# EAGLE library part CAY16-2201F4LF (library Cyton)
Bourns CAY16 Series 2.2k +/-1% Isolated SMT Resistor Array, 4 Resistors, 0.25W total 1206 Package Convex Source: Datasheet

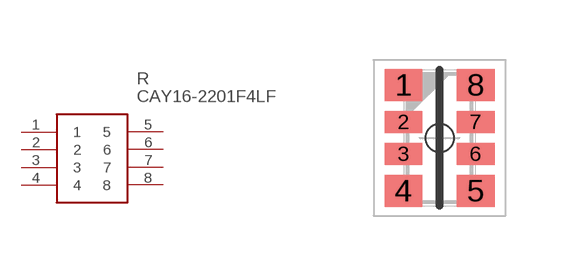
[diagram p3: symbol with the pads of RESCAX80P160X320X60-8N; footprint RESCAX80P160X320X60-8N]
Designator prefix R

## CAY16-2201F4LF (DESCRIPTION: Bourns CAY16 Series 2.2k +/-1% Isolated SMT Resistor Array, 4 Resistors, 0.25W total 1206 Package Convex; HEIGHT: 0.6mm; MANUFACTURER_NAME: Bourns; MANUFACTURER_PART_NUMBER: CAY16-2201F4LF; RS_PART_NUMBER: 7408773P; RS_PRICE-STOCK: http://uk.rs-online.com/web/p/products/7408773P)  [RESCAX80P160X320X60-8N]
1  1
2  2
3  3
4  4
5  5
6  6
7  7
8  8

## Footprint RESCAX80P160X320X60-8N (pad centres in mm)
CAY16-4701F4LF
smd 0.95 x 0.8: 1 -0.9,1.325; 4 -0.9,-1.325; 5 0.9,-1.325; 8 0.9,1.325
smd 0.95 x 0.55: 2 -0.9,0.4; 3 -0.9,-0.4; 6 0.9,-0.4; 7 0.9,0.4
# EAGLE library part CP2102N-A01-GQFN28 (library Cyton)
Ic Bridge Usb To Uart 28qfn

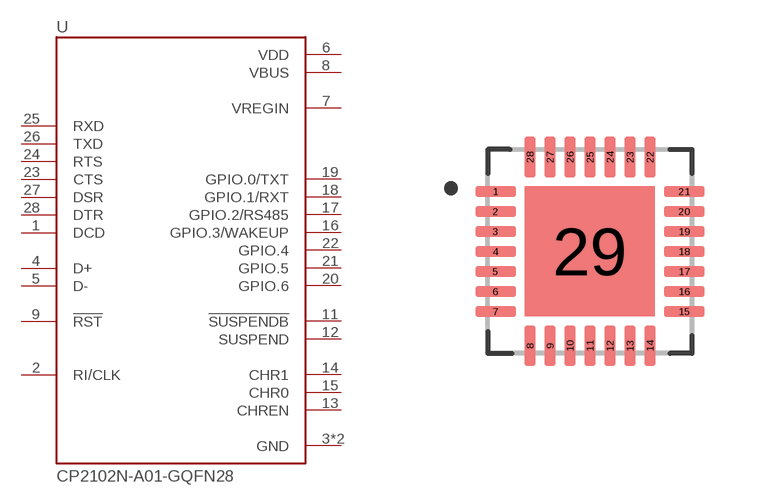
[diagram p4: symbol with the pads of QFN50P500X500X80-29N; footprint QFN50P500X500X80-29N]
Designator prefix U

## CP2102N-A01-GQFN28 (AVAILABILITY: Unavailable; DESCRIPTION: Usb-Uart Interface Bridge, Qfn-28; MF: Silicon Labs; MP: CP2102N-A01-GQFN28; PACKAGE: QFN-28 Silicon Labs; PRICE: None)  [QFN50P500X500X80-29N]
1  DCD  in
2  RI/CLK
3  GND  pwr
4  D+
5  D-
6  VDD  pwr
7  VREGIN  pwr
8  VBUS  pwr
9  !RST  in
11  !SUSPENDB  out
12  SUSPEND  out
13  CHREN  out
14  CHR1  out
15  CHR0  out
16  GPIO.3/WAKEUP
17  GPIO.2/RS485
18  GPIO.1/RXT
19  GPIO.0/TXT
20  GPIO.6
21  GPIO.5
22  GPIO.4
23  CTS  in
24  RTS  out
25  RXD  in
26  TXD  out
27  DSR  in
28  DTR  out
29  GND  pwr

## Footprint QFN50P500X500X80-29N (pad centres in mm)
smd 1.01 x 0.27: 1 -2.36,1.5; 2 -2.36,1; 3 -2.36,0.5; 4 -2.36,0; 5 -2.36,-0.5; 6 -2.36,-1; 7 -2.36,-1.5; 15 2.36,-1.5; 16 2.36,-1; 17 2.36,-0.5; 18 2.36,0; 19 2.36,0.5; 20 2.36,1; 21 2.36,1.5
smd 0.27 x 1.01: 8 -1.5,-2.36; 9 -1,-2.36; 10 -0.5,-2.36; 11 0,-2.36; 12 0.5,-2.36; 13 1,-2.36; 14 1.5,-2.36; 22 1.5,2.36; 23 1,2.36; 24 0.5,2.36; 25 0,2.36; 26 -0.5,2.36; 27 -1,2.36; 28 -1.5,2.36
smd 3.25 x 3.25: 29 0,0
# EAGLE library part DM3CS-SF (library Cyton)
CONN MICRO SD CARD HINGED TYPE

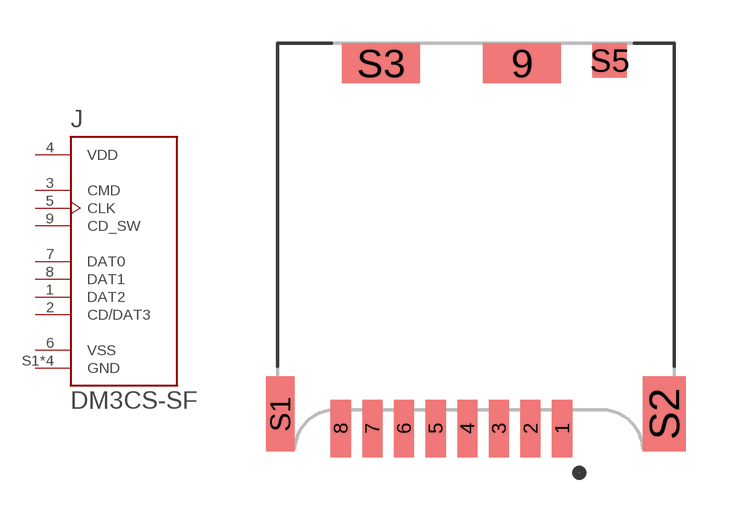
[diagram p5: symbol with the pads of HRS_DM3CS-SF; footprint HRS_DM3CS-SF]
Designator prefix J

## DM3CS-SF (AVAILABILITY: Unavailable; DESCRIPTION: Conn Micro SD Card HDR 8 POS 1.1mm Solder RA SMD Embossed T/R 0.5A; MF: Hirose; MP: DM3CS-SF; PACKAGE: None; PRICE: None)  [HRS_DM3CS-SF]
1  DAT2  pas
2  CD/DAT3  pas
3  CMD  pas
4  VDD  pas
5  CLK  pas
6  VSS  pas
7  DAT0  pas
8  DAT1  pas
9  CD_SW  pas
S1  GND  pas
S2  GND  pas
S3  GND  pas
S5  GND  pas

## Footprint HRS_DM3CS-SF (pad centres in mm)
smd 0.7 x 2: 1 3.2,-6.35; 2 2.1,-6.35; 3 1,-6.35; 4 -0.1,-6.35; 5 -1.2,-6.35; 6 -2.3,-6.35; 7 -3.4,-6.35; 8 -4.5,-6.35
smd 2.7 x 1.4: 9 1.8,6.35; S3 -3.1,6.35
smd 1 x 2.6: S1 -6.6,-5.85
smd 1.5 x 2.6: S2 6.75,-5.85
smd 1.2 x 1.2: S5 4.85,6.45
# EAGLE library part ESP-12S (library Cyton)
AI-Thinker ESP-12S ESP-12S WiFi module is developed by AI-Thinker Co.,Ltd, core processor ESP8266 in smaller sizes of the module encapsulates Tensilica L106 integrates industry-leading ultra low power 32-bit MCU micro, with the 16-bit short mode, clock speed support 80 MHz, 160 MHz, supports the RTOS, integrated Wi-Fi MAC/BB/RF/PA/LNA, on-board antennas.

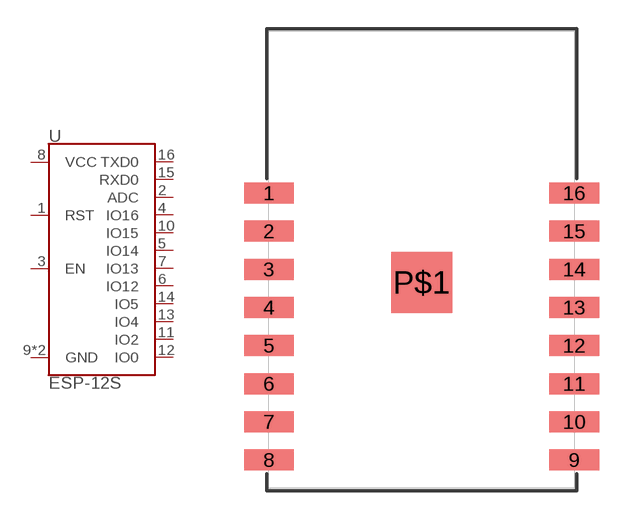
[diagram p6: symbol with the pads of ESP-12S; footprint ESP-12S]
Designator prefix U

## ESP-12S (AVAILABILITY: Unavailable; MF: RF Solutions; MP: ESP-12S; PACKAGE: Module RF Solutions; PRICE: None)  [ESP-12S]
1  RST
2  ADC
3  EN
4  IO16
5  IO14
6  IO12
7  IO13
8  VCC
9  GND
10  IO15
11  IO2
12  IO0
13  IO4
14  IO5
15  RXD0
16  TXD0
P$1  GND

## Footprint ESP-12S (pad centres in mm)
smd 2.6 x 1.1: 1 -8,3.5; 2 -8,1.5; 3 -8,-0.5; 4 -8,-2.5; 5 -8,-4.5; 6 -8,-6.5; 7 -8,-8.5; 8 -8,-10.5; 9 8,-10.5; 10 8,-8.5; 11 8,-6.5; 12 8,-4.5; 13 8,-2.5; 14 8,-0.5; 15 8,1.5; 16 8,3.5
smd 3.2 x 3.2: P$1 0,-1.2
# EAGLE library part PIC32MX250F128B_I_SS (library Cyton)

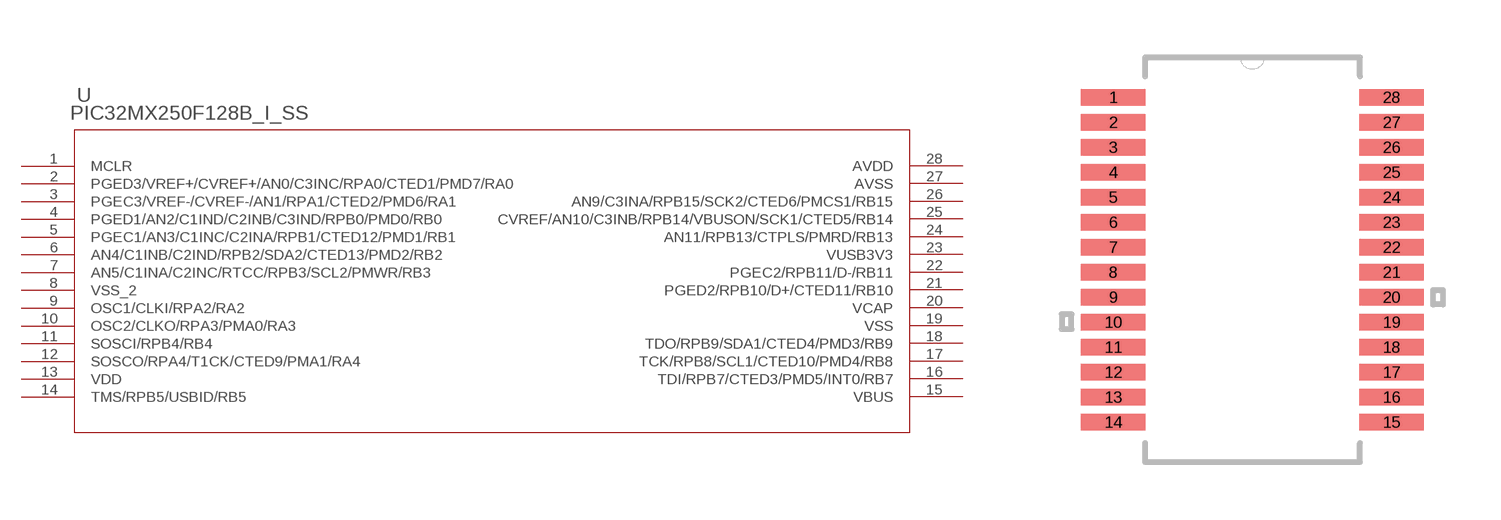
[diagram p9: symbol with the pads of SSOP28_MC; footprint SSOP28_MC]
Designator prefix U

## PIC32MX250F128B_I_SS (AVAILABILITY: Unavailable; DESCRIPTION: PIC32 Series 32 kB RAM 128 KB Flash 19 I/O 32-Bit Microcontroller - SSOP-28; MF: Microchip; MP: PIC32MX250F128B-I/SS; PACKAGE: SSOP-28 Microchip; PRICE: None)  [SSOP28_MC]
1  MCLR  in
2  PGED3/VREF+/CVREF+/AN0/C3INC/RPA0/CTED1/PMD7/RA0
3  PGEC3/VREF-/CVREF-/AN1/RPA1/CTED2/PMD6/RA1
4  PGED1/AN2/C1IND/C2INB/C3IND/RPB0/PMD0/RB0
5  PGEC1/AN3/C1INC/C2INA/RPB1/CTED12/PMD1/RB1
6  AN4/C1INB/C2IND/RPB2/SDA2/CTED13/PMD2/RB2
7  AN5/C1INA/C2INC/RTCC/RPB3/SCL2/PMWR/RB3
8  VSS_2  pwr
9  OSC1/CLKI/RPA2/RA2
10  OSC2/CLKO/RPA3/PMA0/RA3
11  SOSCI/RPB4/RB4
12  SOSCO/RPA4/T1CK/CTED9/PMA1/RA4
13  VDD  pwr
14  TMS/RPB5/USBID/RB5
15  VBUS  pwr
16  TDI/RPB7/CTED3/PMD5/INT0/RB7
17  TCK/RPB8/SCL1/CTED10/PMD4/RB8
18  TDO/RPB9/SDA1/CTED4/PMD3/RB9
19  VSS  pwr
20  VCAP  pwr
21  PGED2/RPB10/D+/CTED11/RB10
22  PGEC2/RPB11/D-/RB11
23  VUSB3V3  pwr
24  AN11/RPB13/CTPLS/PMRD/RB13
25  CVREF/AN10/C3INB/RPB14/VBUSON/SCK1/CTED5/RB14
26  AN9/C3INA/RPB15/SCK2/CTED6/PMCS1/RB15
27  AVSS  pwr
28  AVDD  pwr

## Footprint SSOP28_MC (pad centres in mm)
smd 1.676 x 0.432: 1 -3.617,4.225; 2 -3.617,3.575; 3 -3.617,2.925; 4 -3.617,2.275; 5 -3.617,1.625; 6 -3.617,0.975; 7 -3.617,0.325; 8 -3.617,-0.325; 9 -3.617,-0.975; 10 -3.617,-1.625; 11 -3.617,-2.275; 12 -3.617,-2.925; 13 -3.617,-3.575; 14 -3.617,-4.225; 15 3.617,-4.225; 16 3.617,-3.575; 17 3.617,-2.925; 18 3.617,-2.275; 19 3.617,-1.625; 20 3.617,-0.975; 21 3.617,-0.325; 22 3.617,0.325; 23 3.617,0.975; 24 3.617,1.625; 25 3.617,2.275; 26 3.617,2.925; 27 3.617,3.575; 28 3.617,4.225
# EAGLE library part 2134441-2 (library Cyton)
Conn Micro USB RCP 5 POS 0.65mm Solder RA SMD 5 Terminal 1 Port T/R

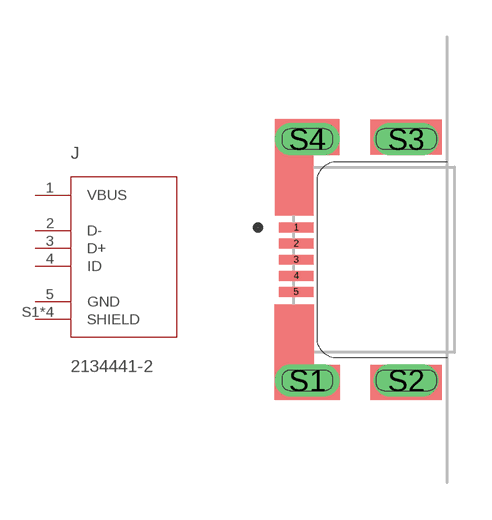
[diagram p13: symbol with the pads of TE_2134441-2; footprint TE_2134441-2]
Designator prefix J

## 2134441-2 (AVAILABILITY: Unavailable; COMMENT: 2134441-2; DESCRIPTION: Conn Micro USB RCP 5 POS 0.65mm Solder RA SMD 5 Terminal 1 Port T/R; MF: TE Connectivity; MP: 2134441-2; PACKAGE: None; PRICE: None; TE_PURCHASE_URL: https://www.te.com/usa-en/product-2134441-2.html?te_bu=Cor&te_type=disp&te_campaign=seda_glo_cor-seda-global-disp-prtnr-fy19-seda-model-bom-cta_sma-317_1&elqCampaignId=32493)  [TE_2134441-2]
1  VBUS  pwr
2  D-
3  D+
4  ID
5  GND  pwr
S1  SHIELD  pwr
S2  SHIELD  pwr
S3  SHIELD  pwr
S4  SHIELD  pwr

## Footprint TE_2134441-2 (pad centres in mm)
smd 1.4 x 0.4: 1 -4.45,1.3; 2 -4.45,0.65; 3 -4.45,0; 4 -4.45,-0.65; 5 -4.45,-1.3
drill 0.8 pad 1.25 long: S1 -4,-4.875; S2 0,-4.875; S3 0,4.875; S4 -4,4.875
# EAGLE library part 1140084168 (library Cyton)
Conn; IC Socket; Micro SD; Right Angle; PCB Mount; MicroSD Ser.

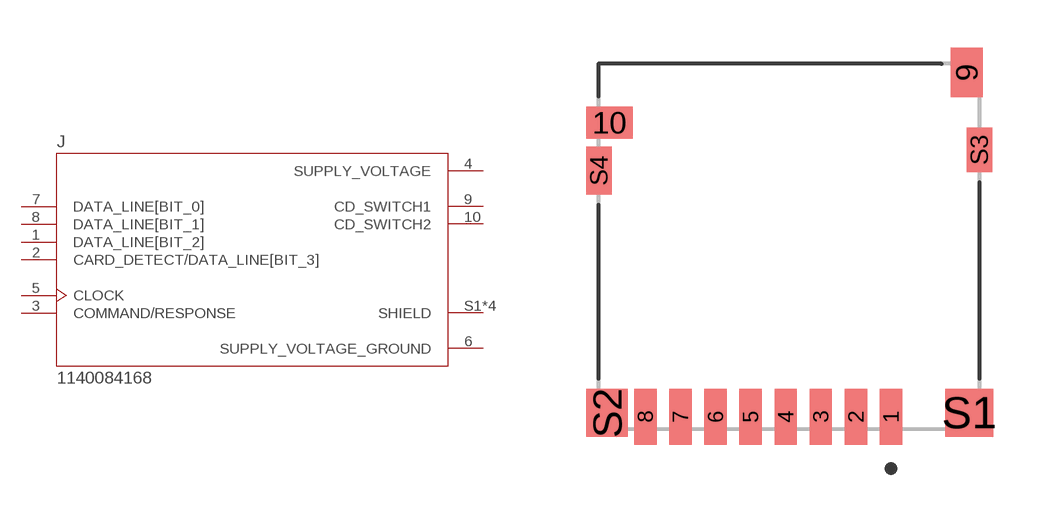
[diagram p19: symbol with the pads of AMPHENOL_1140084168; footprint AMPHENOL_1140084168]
Designator prefix J

## 1140084168 (AVAILABILITY: Unavailable; DESCRIPTION: 10 _8 + 2_ Position Card Connector Secure Digital - microSD™ Surface Mount, Right Angle Gold; MF: Amphenol ICC; MP: 1140084168; PACKAGE: None; PRICE: None)  [AMPHENOL_1140084168]
1  DATA_LINE[BIT_2]
2  CARD_DETECT/DATA_LINE[BIT_3]
3  COMMAND/RESPONSE
4  SUPPLY_VOLTAGE  pwr
5  CLOCK
6  SUPPLY_VOLTAGE_GROUND  pwr
7  DATA_LINE[BIT_0]
8  DATA_LINE[BIT_1]
9  CD_SWITCH1
10  CD_SWITCH2
S1  SHIELD  pas
S2  SHIELD  pas
S3  SHIELD  pas
S4  SHIELD  pas

## Footprint AMPHENOL_1140084168 (pad centres in mm)
smd 0.7 x 1.75: 1 3.2,-0.875; 2 2.1,-0.875; 3 1,-0.875; 4 -0.1,-0.875; 5 -1.2,-0.875; 6 -2.3,-0.875; 7 -3.4,-0.875; 8 -4.5,-0.875
smd 1 x 1.55: 9 5.575,9.925
smd 1.45 x 1: 10 -5.625,8.35
smd 1.5 x 1.5: S1 5.65,-0.75
smd 1.3 x 1.5: S2 -5.7,-0.75
smd 0.8 x 1.4: S3 5.975,7.5
smd 0.8 x 1.5: S4 -5.95,6.85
